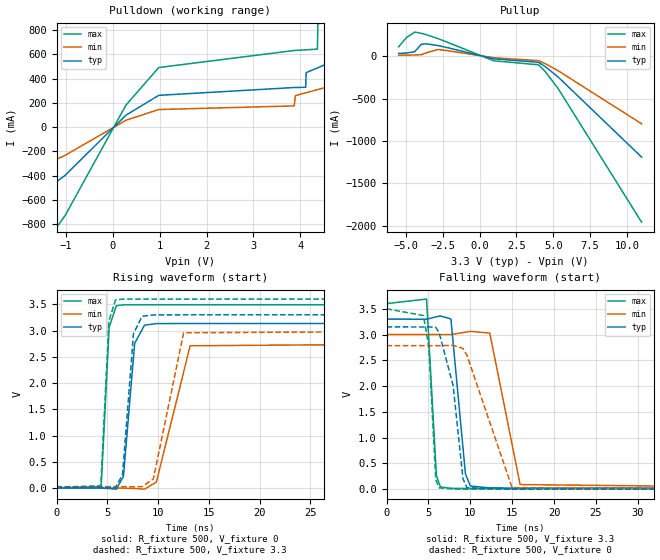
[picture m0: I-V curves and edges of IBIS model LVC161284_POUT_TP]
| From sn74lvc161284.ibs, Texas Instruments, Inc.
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[Model]   LVC161284_POUT_TP
Model_type  Output
Vref =   0
Rref =   500
Cref =   50p
Vmeas =   1.5
| variable   typ   min   max
C_comp   8.49pF   4.90pF   13.50pF
| C_pullup   7.92pF   4.90pF   9.61pF
| C_pulldown   9.06pF   6.12pF   13.50pF
[Temperature Range]   40   100   -40
| Ambient temperature   25   85   -40
[Voltage range]   3.3   3   3.6
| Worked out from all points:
|   slope of the pulldown table from 0 to 0.495 V, typ, clamps not added: 3.07 ohm
|   slope of the pullup table from 0 to 0.495 V, typ, clamps not added: 25.9 ohm
|   rising waveform, R_fixture 500, V_fixture 0: 20-80 % time 726ps typ, 1.28ns min, 434ps max; typ from 0 V to 3.13 V
|   falling waveform, R_fixture 500, V_fixture 3.3: 20-80 % time 1.05ns typ, 1.75ns min, 628ps max; typ from 3.3 V to 0.019 V
|   rising waveform, R_fixture 500, V_fixture 3.3: 20-80 % time 704ps typ, 1.22ns min, 431ps max; typ from 0.017 V to 3.3 V
|   falling waveform, R_fixture 500, V_fixture 0: 20-80 % time 1.8ns typ, 3.72ns min, 682ps max; typ from 3.15 V to 0 V
[Pulldown]
| LVC161284_POUT_TP
|   Voltage   I(typ)   I(min)   I(max)
-5.5V     -1.269A    -787mA     -2.244A
-1.8V     -627mA     -368.2mA   -1.148A
-1.02V    -398.3mA   -233.1mA   -730.6mA
280mV     98.53mA    56.64mA    181.1mA
980mV     262mA      145.2mA    491.3mA
3.87V     326.6mA    175.1mA    631.7mA
3.895V    326.7mA    259.6mA    632.1mA
4.115V    328.5mA    283mA      637.2mA
4.125V    449.6mA    284mA      637.4mA
4.365V    488mA      308.8mA    643mA
4.375V    489.6mA    309.9mA    848.3mA
11V       1.573A     1.016A     2.642A
[Pullup]
| LVC161284_POUT_TP
|   Voltage   I(typ)   I(min)   I(max)
-5.5V     31.13mA    9.815mA    109mA
-4.98V    35.47mA    10.6mA     216.5mA
-4.41V    50.69mA    12.41mA    281.8mA
-3.96V    138.9mA    16.14mA    267.2mA
-3.6V     143.2mA    38.58mA    250.2mA
-2.835V   123.2mA    76.78mA    205.4mA
-2.205V   99.16mA    63.58mA    162.9mA
950mV     -32.79mA   -20.04mA   -56.15mA
4V        -74.35mA   -54.51mA   -103.2mA
4.465V    -125.6mA   -91.02mA   -185.1mA
5.325V    -245.9mA   -172.6mA   -381.5mA
11V       -1.19A     -797.5mA   -1.956A
[Ramp]
| LVC161284_POUT_TP
| variable   typ   min   max
dV/dt_r   1.89/7.34E-10   1.67/1.29E-09   2.11/4.40E-10
dV/dt_f   2.06/1.10E-09   1.87/1.85E-09   2.21/6.50E-10
R_load = 500
[Rising Waveform]
| LVC161284_POUT_TP
R_fixture =   500
C_fixture =   0
L_fixture =   0
V_fixture =   0
V_fixture_min = 0
V_fixture_max = 0
|   Time   V(typ)   V(min)   V(max)
0s        1.926nV    14.82nV    84.37pV
4.395ns   -508.1uV   -18.9uV    25.85mV
5.185ns   -9.223mV   116.7uV    3.065V
5.885ns   -21.87mV   324.6uV    3.473V
6.59ns    221.7mV    -1.645mV   3.49V
7.695ns   2.755V     -9.451mV   3.491V
8.665ns   3.103V     -21.5mV    3.492V
9.835ns   3.132V     112.3mV    3.492V
13.16ns   3.135V     2.71V      3.492V
50ns      3.135V     2.762V     3.492V
[Falling Waveform]
| LVC161284_POUT_TP
R_fixture =   500
C_fixture =   0
L_fixture =   0
V_fixture =   3.3
V_fixture_min = 3
V_fixture_max = 3.6
|   Time   V(typ)   V(min)   V(max)
0s        3.3V       3V         3.6V
4.78ns    3.296V     3V         3.688V
5.955ns   3.345V     3V         263mV
6.43ns    3.36V      2.999V     42.57mV
7.685ns   3.302V     2.999V     16.94mV
9.42ns    293.4mV    3.046V     13.43mV
10.01ns   61.9mV     3.062V     13.11mV
12.32ns   23.77mV    3.028V     12.42mV
15.95ns   20.25mV    89.45mV    11.96mV
50ns      19.07mV    30.02mV    11.34mV
[Rising Waveform]
| LVC161284_POUT_TP
R_fixture =   500
C_fixture =   0
L_fixture =   0
V_fixture =   3.3
V_fixture_min = 3
V_fixture_max = 3.6
|   Time   V(typ)   V(min)   V(max)
0s        17.15mV    26.87mV    10.4mV
4.36ns    16.8mV     26.85mV    43.81mV
5.16ns    10.95mV    26.96mV    3.184V
5.805ns   8.764mV    27.06mV    3.582V
6.5ns     254.5mV    25.69mV    3.599V
7.58ns    2.942V     22.89mV    3.6V
8.42ns    3.271V     25.41mV    3.6V
9.53ns    3.297V     170.6mV    3.6V
12.52ns   3.3V       2.957V     3.6V
50ns      3.3V       3V         3.6V
[Falling Waveform]
| LVC161284_POUT_TP
R_fixture =   500
C_fixture =   0
L_fixture =   0
V_fixture =   0
V_fixture_min = 0
V_fixture_max = 0
|   Time   V(typ)   V(min)   V(max)
0s        3.148V     2.784V     3.5V
4.41ns    3.146V     2.784V     3.368V
5.04ns    3.148V     2.784V     2.774V
5.88ns    3.14V      2.784V     184.6mV
6.285ns   3.033V     2.783V     25.49mV
7.95ns    2.008V     2.79V      3.014mV
9.125ns   203.9mV    2.73V      1.567mV
9.6ns     28.76mV    2.597V     1.346mV
14.99ns   297.5uV    29.03mV    444.1uV
50ns      13.22uV    29.36uV    6.238uV
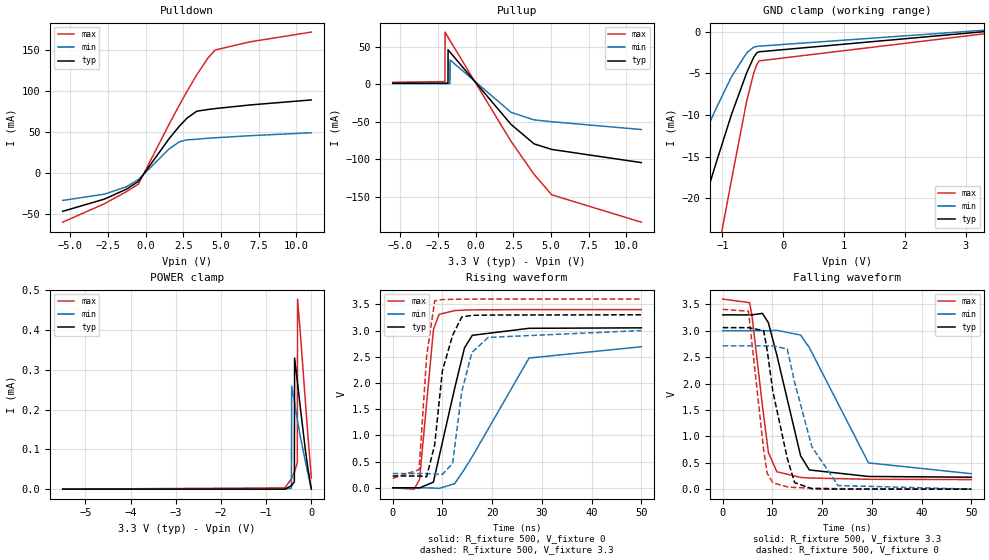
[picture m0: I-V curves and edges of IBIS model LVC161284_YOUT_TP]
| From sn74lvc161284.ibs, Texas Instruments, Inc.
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[Model]   LVC161284_YOUT_TP
Model_type  3-state
Enable   Active-Low
Vref =   0
Rref =   62
Cref =   50p
Vmeas =   1.4
| variable   typ   min   max
C_comp   3.92pF   3.60pF   4.27pF
| C_pullup   2.97pF   1.95pF   4.21pF
| C_pulldown   3.37pF   3.03pF   4.14pF
| C_tri-state   3.92pF   3.60pF   4.27pF
[Temperature Range]   40   100   -40
| Ambient temperature   25   85   -40
[Voltage range]   3.3   3   3.6
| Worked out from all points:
|   slope of the pulldown table from 0 to 0.495 V, typ, clamps not added: 37.8 ohm
|   slope of the pullup table from 0 to 0.495 V, typ, clamps not added: 40.9 ohm
|   rising waveform, R_fixture 500, V_fixture 0: 20-80 % time 4.45ns typ, 9.29ns min, 1.97ns max; typ from 0 V to 3.05 V
|   falling waveform, R_fixture 500, V_fixture 3.3: 20-80 % time 4.6ns typ, 8.37ns min, 2.62ns max; typ from 3.3 V to 0.227 V
|   rising waveform, R_fixture 500, V_fixture 3.3: 20-80 % time 2.6ns typ, 2.74ns min, 1.57ns max; typ from 0.225 V to 3.3 V
|   falling waveform, R_fixture 500, V_fixture 0: 20-80 % time 3.73ns typ, 5.12ns min, 2.31ns max; typ from 3.06 V to 0 V
[GND Clamp]
| LVC161284_YOUT_TP
|   Voltage   I(typ)   I(min)   I(max)
-5.5V     -142.1mA   -99.43mA   -215.9mA
-2.265V   -46.37mA   -30.73mA   -74.31mA
-2.185V   -44.13mA   -29.13mA   -70.97mA
-1.685V   -30.47mA   -19.42mA   -50.47mA
-1.195V   -17.9mA    -10.67mA   -31.15mA
-1.14V    -16.57mA   -9.764mA   -29.03mA
-850mV    -9.911mA   -5.389mA   -17.74mA
-600mV    -4.914mA   -2.538mA   -8.294mA
-485mV    -3.066mA   -1.848mA   -4.955mA
-435mV    -2.546mA   -1.777mA   -3.97mA
-395mV    -2.411mA   -1.736mA   -3.499mA
3.3V      141.7pA    168.7uA    -261.4uA
[POWER Clamp]
| LVC161284_YOUT_TP
|   Voltage   I(typ)   I(min)   I(max)
-5.5V     46.85nA    131.5nA    6.158nA
-585mV    12.19nA    2.675nA    3.285uA
-440mV    8.724uA    2.432uA    26.26uA
-435mV    9.268uA    259.4uA    27.35uA
-375mV    19.07uA    220.6uA    42.01uA
-370mV    330uA      217.2uA    43.39uA
-310mV    273uA      175.6uA    67.35uA
-305mV    267.9uA    172.1uA    478.3uA
-250mV    212.1uA    135.7uA    403.5uA
-130mV    96.77uA    68.64uA    218.4uA
-70mV     47.77uA    37uA       127.7uA
-95.1fV   141.7pA    739.8pA    27.84uA
[Pulldown]
| LVC161284_YOUT_TP
|   Voltage   I(typ)   I(min)   I(max)
-5.5V     -46.7mA    -33.42mA   -59.97mA
-2.72V    -31.74mA   -25.77mA   -37.32mA
-1.275V   -19.72mA   -16.73mA   -22.76mA
-480mV    -10.32mA   -8.029mA   -13.64mA
1.565V    41.96mA    29.5mA     59.61mA
2.25V     57.29mA    38.13mA    83.15mA
2.75V     66.96mA    40.53mA    99.64mA
3.395V    75.38mA    41.18mA    119.7mA
4.12V     77.46mA    42.37mA    139.8mA
4.62V     78.59mA    43mA       150.1mA
6.93V     83.02mA    45.54mA    160mA
11V       89.16mA    49.12mA    171.9mA
[Pullup]
| LVC161284_YOUT_TP
|   Voltage   I(typ)   I(min)   I(max)
-5.5V     1.154mA    597.1uA    2.358mA
-2.055V   1.148mA    588.5uA    3.334mA
-2.03V    1.148mA    588.3uA    4.267mA
-2.025V   1.148mA    588.3uA    69.26mA
-1.83V    1.545mA    586.5uA    62.56mA
-1.825V   45.79mA    586.4uA    62.39mA
-1.7V     42.63mA    625uA      58.09mA
-1.695V   42.5mA     32.17mA    57.92mA
2.35V     -53.62mA   -37.61mA   -76.28mA
3.88V     -79.61mA   -47.69mA   -120.2mA
5.05V     -87.05mA   -50.14mA   -147.5mA
11V       -104.6mA   -60.54mA   -184mA
[Ramp]
| LVC161284_YOUT_TP
| variable   typ   min   max
dV/dt_r   1.84/4.48E-09   1.62/9.36E-09   2.06/1.98E-09
dV/dt_f   1.86/4.64E-09   1.65/8.51E-09   2.07/2.63E-09
R_load = 500
[Rising Waveform]
| LVC161284_YOUT_TP
R_fixture =   500
C_fixture =   0
L_fixture =   0
V_fixture =   0
V_fixture_min = 0
V_fixture_max = 0
|   Time   V(typ)   V(min)   V(max)
0s        55.26nV    325.9nV    3.013nV
4.305ns   -40.52uV   1.053uV    -26.73mV
5.4ns     -2.854mV   -22.97uV   158.8mV
8.19ns    107.9mV    -5.055mV   3.015V
9.335ns   592.3mV    -12.18mV   3.309V
12.47ns   1.901V     78.25mV    3.38V
14.43ns   2.667V     355.3mV    3.39V
16.01ns   2.909V     594.7mV    3.394V
27.42ns   3.042V     2.475V     3.399V
50ns      3.051V     2.69V      3.399V
[Falling Waveform]
| LVC161284_YOUT_TP
R_fixture =   500
C_fixture =   0
L_fixture =   0
V_fixture =   3.3
V_fixture_min = 3
V_fixture_max = 3.6
|   Time   V(typ)   V(min)   V(max)
0s        3.3V       3V         3.599V
5.4ns     3.299V     3V         3.531V
5.86ns    3.299V     3V         3.308V
7.985ns   3.329V     3V         1.584V
9.185ns   3.151V     2.999V     694.9mV
10.89ns   2.537V     3.007V     330.1mV
15.67ns   630.8mV    2.917V     222.9mV
17.43ns   363.8mV    2.679V     212mV
29.32ns   240.6mV    498mV      187.2mV
50ns      226.9mV    293.2mV    181.6mV
[Rising Waveform]
| LVC161284_YOUT_TP
R_fixture =   500
C_fixture =   0
L_fixture =   0
V_fixture =   3.3
V_fixture_min = 3
V_fixture_max = 3.6
|   Time   V(typ)   V(min)   V(max)
0s        225.3mV    271.6mV    181mV
5.305ns   224.6mV    271.6mV    345.1mV
6.825ns   209.9mV    271.7mV    2.508V
8.445ns   819.6mV    262.3mV    3.566V
9.99ns    2.231V     255.1mV    3.591V
12.06ns   2.911V     467mV      3.596V
13.88ns   3.257V     1.828V     3.598V
15.92ns   3.289V     2.579V     3.599V
19.22ns   3.295V     2.869V     3.6V
50ns      3.3V       2.999V     3.6V
[Falling Waveform]
| LVC161284_YOUT_TP
R_fixture =   500
C_fixture =   0
L_fixture =   0
V_fixture =   0
V_fixture_min = 0
V_fixture_max = 0
|   Time   V(typ)   V(min)   V(max)
0s        3.058V     2.712V     3.404V
5.18ns    3.058V     2.712V     3.369V
8.235ns   3.002V     2.712V     741.6mV
8.945ns   2.628V     2.713V     301.7mV
10.09ns   1.849V     2.713V     119.9mV
12.99ns   581.5mV    2.654V     43.58mV
14.46ns   125.3mV    2.023V     32.78mV
17.94ns   6.954mV    801.7mV    19.28mV
23.2ns    1.639mV    69.13mV    10.17mV
50ns      192.9uV    595.3uV    732.7uV
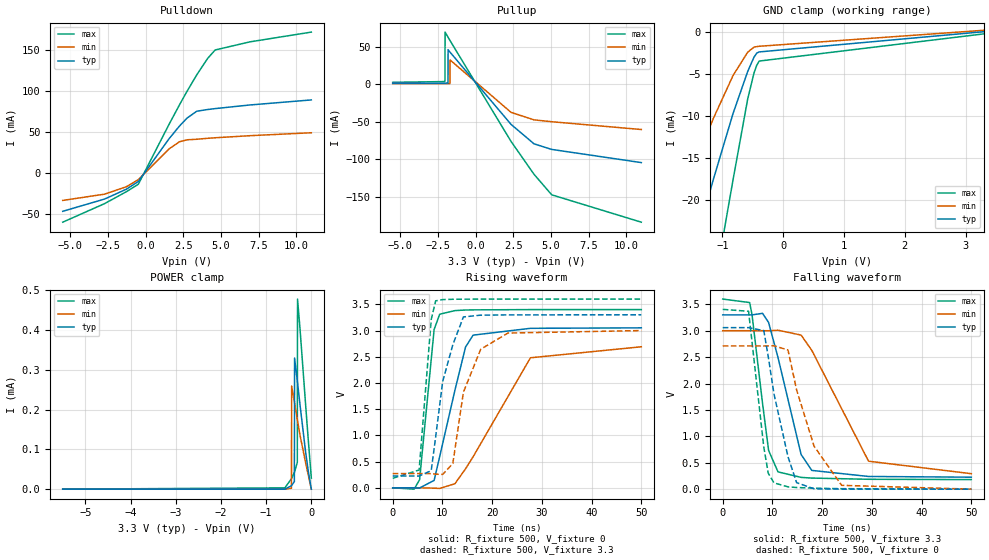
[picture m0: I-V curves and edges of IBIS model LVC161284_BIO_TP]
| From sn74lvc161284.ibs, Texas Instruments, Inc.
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[Model]   LVC161284_BIO_TP
Model_type  I/O
Vinl=0.8
Vinh=2.0
Enable   Active-Low
Vref = 0
Rref = 62
Cref = 50p
Vmeas= 1.4
| variable   typ   min   max
C_comp   4.99pF   4.39pF   5.65pF
| C_pullup   4.04pF   2.78pF   5.07pF
| C_pulldown   4.43pF   3.88pF   5.14pF
| C_tri-state   4.99pF   4.39pF   5.65pF
[Temperature Range]   40   100   -40
| Ambient temperature   25   85   -40
[Voltage range]   3.3   3   3.6
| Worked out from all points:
|   slope of the pulldown table from 0 to 0.495 V, typ, clamps not added: 37.8 ohm
|   slope of the pullup table from 0 to 0.495 V, typ, clamps not added: 40.9 ohm
|   rising waveform, R_fixture 500, V_fixture 0: 20-80 % time 4.59ns typ, 9.47ns min, 2.08ns max; typ from 0 V to 3.05 V
|   falling waveform, R_fixture 500, V_fixture 3.3: 20-80 % time 4.63ns typ, 8.4ns min, 2.65ns max; typ from 3.3 V to 0.227 V
|   rising waveform, R_fixture 500, V_fixture 3.3: 20-80 % time 3.44ns typ, 3.82ns min, 1.74ns max; typ from 0.225 V to 3.3 V
|   falling waveform, R_fixture 500, V_fixture 0: 20-80 % time 3.89ns typ, 5.79ns min, 2.37ns max; typ from 3.06 V to 0 V
[GND Clamp]
| LVC161284_BIO_TP
|   Voltage   I(typ)   I(min)   I(max)
-5.5V     -150.9mA   -105.1mA   -231.1mA
-2.265V   -49.03mA   -32.34mA   -79.17mA
-1.755V   -34.12mA   -21.78mA   -56.65mA
-1.685V   -32.13mA   -20.38mA   -53.62mA
-1.205V   -19.04mA   -11.32mA   -33.36mA
-1.15V    -17.62mA   -10.35mA   -31.1mA
-825mV    -9.746mA   -5.218mA   -17.63mA
-585mV    -4.755mA   -2.446mA   -8.044mA
-480mV    -3.025mA   -1.842mA   -4.908mA
-435mV    -2.549mA   -1.781mA   -3.991mA
-395mV    -2.411mA   -1.738mA   -3.5mA
3.3V      150.7pA    168.7uA    -261.4uA
[POWER Clamp]
| LVC161284_BIO_TP
|   Voltage   I(typ)   I(min)   I(max)
-5.5V     46.88nA    131.6nA    6.247nA
-585mV    12.2nA     2.725nA    3.285uA
-440mV    8.724uA    2.432uA    26.26uA
-435mV    9.268uA    259.4uA    27.35uA
-375mV    19.07uA    220.6uA    42.01uA
-370mV    330uA      217.2uA    43.39uA
-310mV    273uA      175.6uA    67.35uA
-305mV    267.9uA    172.1uA    478.3uA
-250mV    212.1uA    135.7uA    403.5uA
-130mV    96.77uA    68.64uA    218.4uA
-70mV     47.77uA    37uA       127.7uA
-95.1fV   150.7pA    776.1pA    27.84uA
[Pulldown]
| LVC161284_BIO_TP
|   Voltage   I(typ)   I(min)   I(max)
-5.5V     -46.7mA    -33.42mA   -59.97mA
-2.72V    -31.74mA   -25.77mA   -37.32mA
-1.275V   -19.72mA   -16.73mA   -22.76mA
-480mV    -10.32mA   -8.029mA   -13.64mA
1.565V    41.96mA    29.5mA     59.61mA
2.25V     57.29mA    38.13mA    83.15mA
2.75V     66.96mA    40.53mA    99.64mA
3.395V    75.38mA    41.18mA    119.7mA
4.12V     77.46mA    42.37mA    139.8mA
4.62V     78.59mA    43mA       150.1mA
6.93V     83.02mA    45.54mA    160mA
11V       89.16mA    49.12mA    171.9mA
[Pullup]
| LVC161284_BIO_TP
|   Voltage   I(typ)   I(min)   I(max)
-5.5V     1.154mA    597.1uA    2.358mA
-2.055V   1.148mA    588.5uA    3.334mA
-2.03V    1.148mA    588.3uA    4.267mA
-2.025V   1.148mA    588.3uA    69.26mA
-1.83V    1.545mA    586.5uA    62.56mA
-1.825V   45.79mA    586.4uA    62.39mA
-1.7V     42.63mA    625uA      58.09mA
-1.695V   42.5mA     32.17mA    57.92mA
2.35V     -53.62mA   -37.61mA   -76.28mA
3.88V     -79.61mA   -47.69mA   -120.2mA
5.05V     -87.05mA   -50.14mA   -147.5mA
11V       -104.6mA   -60.54mA   -184mA
[Ramp]
| LVC161284_BIO_TP
| variable   typ   min   max
dV/dt_r   1.84/4.62E-09   1.62/9.55E-09   2.06/2.09E-09
dV/dt_f   1.86/4.68E-09   1.65/8.54E-09   2.07/2.67E-09
R_load = 500
[Rising Waveform]
| LVC161284_BIO_TP
R_fixture =   500
C_fixture =   0
L_fixture =   0
V_fixture =   0
V_fixture_min = 0
V_fixture_max = 0
|   Time   V(typ)   V(min)   V(max)
0s        55.26nV    325.9nV    2.821nV
4.315ns   -17.41uV   1.352uV    -25.92mV
5.41ns    -2.874mV   -6.257uV   155.8mV
8.33ns    141mV      -6.954mV   3.02V
9.445ns   594.2mV    -12.18mV   3.311V
12.51ns   1.86V      77.8mV     3.38V
14.65ns   2.685V     363.2mV    3.391V
16.17ns   2.912V     592.1mV    3.394V
27.7ns    3.042V     2.48V      3.399V
50ns      3.051V     2.69V      3.399V
[Falling Waveform]
| LVC161284_BIO_TP
R_fixture =   500
C_fixture =   0
L_fixture =   0
V_fixture =   3.3
V_fixture_min = 3
V_fixture_max = 3.6
|   Time   V(typ)   V(min)   V(max)
0s        3.3V       3V         3.599V
5.42ns    3.3V       3V         3.533V
5.905ns   3.299V     3V         3.297V
8.005ns   3.329V     3V         1.628V
9.23ns    3.155V     2.999V     733.2mV
11.12ns   2.493V     3.009V     327.3mV
15.77ns   655.9mV    2.917V     223.1mV
17.92ns   355.3mV    2.627V     210.2mV
29.33ns   240.7mV    529.7mV    187.3mV
50ns      226.9mV    293.3mV    181.6mV
[Rising Waveform]
| LVC161284_BIO_TP
R_fixture =   500
C_fixture =   0
L_fixture =   0
V_fixture =   3.3
V_fixture_min = 3
V_fixture_max = 3.6
|   Time   V(typ)   V(min)   V(max)
0s        225.3mV    271.6mV    181mV
5.31ns    224.6mV    271.6mV    339.8mV
7.74ns    326.9mV    271.9mV    3.208V
8.64ns    969.2mV    260.5mV    3.566V
10.04ns   2.023V     255.2mV    3.59V
12.09ns   2.729V     463.4mV    3.596V
14.22ns   3.259V     1.823V     3.598V
17.7ns    3.293V     2.643V     3.599V
23.18ns   3.298V     2.952V     3.6V
50ns      3.3V       2.999V     3.6V
[Falling Waveform]
| LVC161284_BIO_TP
R_fixture =   500
C_fixture =   0
L_fixture =   0
V_fixture =   0
V_fixture_min = 0
V_fixture_max = 0
|   Time   V(typ)   V(min)   V(max)
0s        3.058V     2.712V     3.404V
5.2ns     3.058V     2.712V     3.368V
8.265ns   3.001V     2.712V     794.4mV
9.16ns    2.509V     2.712V     302.2mV
10.31ns   1.803V     2.714V     119.1mV
13.13ns   614.5mV    2.635V     44.05mV
14.87ns   123.4mV    1.877V     31.52mV
18.38ns   6.823mV    812.3mV    18.69mV
23.92ns   1.546mV    72.69mV    9.585mV
50ns      195.8uV    607.8uV    749.5uV
